# Hand-written edge cases for the #43 parser gate: valid for both Limbo and DesignReader.
VERSION 5.8 ;

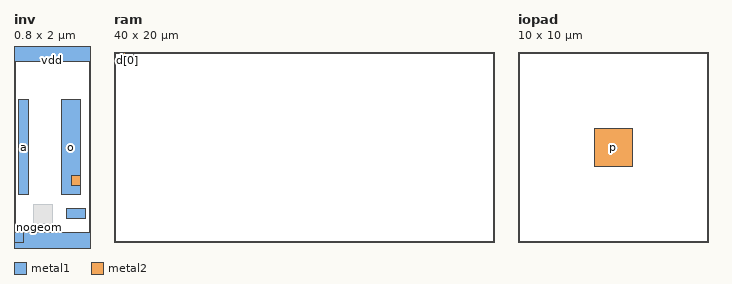
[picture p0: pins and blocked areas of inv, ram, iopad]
MACRO inv
  CLASS CORE ;
  ORIGIN 0 0 ;
  FOREIGN inv 0 0 ;
  SIZE 0.8 BY 2.0 ;
  SYMMETRY X Y ;
  SITE core ;
  PROPERTY LEF58_EDGETYPE "EDGETYPE LEFT 1 ; EDGETYPE RIGHT 1 ;" ;
  PIN a DIRECTION INPUT ;
    USE SIGNAL ;
    PORT
      LAYER metal1 ;
      RECT MASK 1 0.05 0.5 0.15 1.5 ;
      RECT 0.0 0.0 0.1 0.1 ;
    END
    PORT
      LAYER metal2 ;
      RECT 0.6 0.6 0.7 0.7 ;
    END
  END a
  PIN o DIRECTION OUTPUT ;
    PORT
      LAYER metal1 ;
      POLYGON 0.5 0.5 0.7 0.5 0.7 1.5 0.5 1.5 ;
      RECT 0.55 0.25 0.75 0.35 ;
    END
  END o
  PIN vdd
    DIRECTION INOUT ;
    USE POWER ;
    SHAPE ABUTMENT ;
    PORT
      LAYER metal1 ;
      RECT 0.0 1.9 0.8 2.1 ;
    END
  END vdd
  PIN vss
    USE GROUND ;
    PORT
      LAYER metal1 ;
      RECT 0.0 -0.1 0.8 0.1 ;
    END
  END vss
  PIN nogeom DIRECTION INPUT ;
    PORT
      LAYER metal1 ;
      POLYGON 0.1 0.1 0.2 0.1 0.2 0.2 ;
    END
  END nogeom
  OBS
    LAYER metal1 ;
      RECT 0.2 0.2 0.4 0.4 ;
  END
END inv

MACRO ram
  CLASS BLOCK ;
  SIZE 40.0 BY 20.0 ;
  PIN d[0]
    DIRECTION INPUT ;
    PORT
      LAYER metal2 ;
      RECT 1.0 19.0 1.2 20.0 ;
    END
  END d[0]
  PIN q[0]
    DIRECTION OUTPUT ;
    PORT
      LAYER metal2 ;
      RECT 2.0 19.0 2.2 20.0 ;
    END
  END q[0]
END ram

MACRO iopad
  CLASS PAD INPUT ;
  SIZE 10.0 BY 10.0 ;
  SITE pad ;
  PIN p
    DIRECTION INPUT ;
    PORT
      LAYER metal2 ;
      RECT 4.0 4.0 6.0 6.0 ;
    END
  END p
END iopad

MACRO filler1
  CLASS CORE SPACER ;
  SIZE 0.2 BY 2.0 ;
END filler1

MACRO nosize
  CLASS COVER ;
END nosize

END LIBRARY
